VERSION 5.7 ;
  NOWIREEXTENSIONATPIN ON ;
  DIVIDERCHAR "/" ;
  BUSBITCHARS "[]" ;
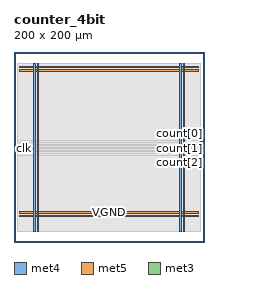
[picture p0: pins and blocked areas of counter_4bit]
MACRO counter_4bit
  CLASS BLOCK ;
  FOREIGN counter_4bit ;
  ORIGIN 0.000 0.000 ;
  SIZE 200.000 BY 200.000 ;
  PIN VGND
    DIRECTION INOUT ;
    USE GROUND ;
    PORT
      LAYER met4 ;
        RECT 24.340 10.640 25.940 187.920 ;
    END
    PORT
      LAYER met4 ;
        RECT 177.940 10.640 179.540 187.920 ;
    END
    PORT
      LAYER met5 ;
        RECT 5.280 30.030 194.360 31.630 ;
    END
    PORT
      LAYER met5 ;
        RECT 5.280 183.210 194.360 184.810 ;
    END
  END VGND
  PIN VPWR
    DIRECTION INOUT ;
    USE POWER ;
    PORT
      LAYER met4 ;
        RECT 21.040 10.640 22.640 187.920 ;
    END
    PORT
      LAYER met4 ;
        RECT 174.640 10.640 176.240 187.920 ;
    END
    PORT
      LAYER met5 ;
        RECT 5.280 26.730 194.360 28.330 ;
    END
    PORT
      LAYER met5 ;
        RECT 5.280 179.910 194.360 181.510 ;
    END
  END VPWR
  PIN clk
    DIRECTION INPUT ;
    USE SIGNAL ;
    ANTENNAGATEAREA 0.852000 ;
    PORT
      LAYER met3 ;
        RECT 0.000 98.640 4.000 99.240 ;
    END
  END clk
  PIN count[0]
    DIRECTION OUTPUT ;
    USE SIGNAL ;
    ANTENNADIFFAREA 0.445500 ;
    PORT
      LAYER met3 ;
        RECT 196.000 105.440 200.000 106.040 ;
    END
  END count[0]
  PIN count[1]
    DIRECTION OUTPUT ;
    USE SIGNAL ;
    ANTENNADIFFAREA 0.445500 ;
    PORT
      LAYER met3 ;
        RECT 196.000 98.640 200.000 99.240 ;
    END
  END count[1]
  PIN count[2]
    DIRECTION OUTPUT ;
    USE SIGNAL ;
    ANTENNADIFFAREA 0.445500 ;
    PORT
      LAYER met3 ;
        RECT 196.000 91.840 200.000 92.440 ;
    END
  END count[2]
  PIN count[3]
    DIRECTION OUTPUT ;
    USE SIGNAL ;
    ANTENNADIFFAREA 0.445500 ;
    PORT
      LAYER met3 ;
        RECT 196.000 102.040 200.000 102.640 ;
    END
  END count[3]
  PIN rst_n
    DIRECTION INPUT ;
    USE SIGNAL ;
    ANTENNAGATEAREA 0.196500 ;
    PORT
      LAYER met3 ;
        RECT 196.000 95.240 200.000 95.840 ;
    END
  END rst_n
  OBS
      LAYER nwell ;
        RECT 5.330 10.795 194.310 187.870 ;
      LAYER li1 ;
        RECT 5.520 10.795 194.120 187.765 ;
      LAYER met1 ;
        RECT 5.520 10.640 194.120 187.920 ;
      LAYER met2 ;
        RECT 21.070 10.695 192.190 187.865 ;
      LAYER met3 ;
        RECT 4.000 106.440 196.000 187.845 ;
        RECT 4.000 105.040 195.600 106.440 ;
        RECT 4.000 103.040 196.000 105.040 ;
        RECT 4.000 101.640 195.600 103.040 ;
        RECT 4.000 99.640 196.000 101.640 ;
        RECT 4.400 98.240 195.600 99.640 ;
        RECT 4.000 96.240 196.000 98.240 ;
        RECT 4.000 94.840 195.600 96.240 ;
        RECT 4.000 92.840 196.000 94.840 ;
        RECT 4.000 91.440 195.600 92.840 ;
        RECT 4.000 10.715 196.000 91.440 ;
  END
END counter_4bit
END LIBRARY

